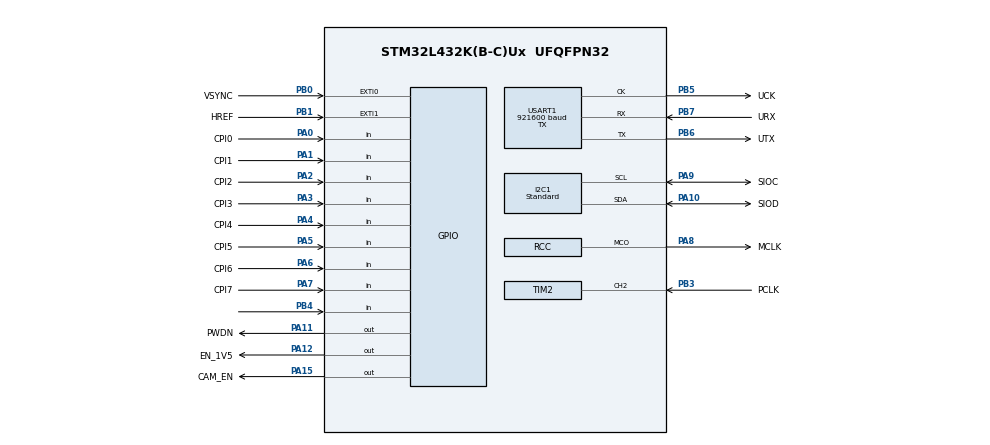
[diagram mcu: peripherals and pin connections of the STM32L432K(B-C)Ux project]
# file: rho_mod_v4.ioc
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Dma.Request0=TIM2_CH2/CH4
Dma.Request1=USART1_TX
Dma.TIM2_CH2/CH4.0.Direction=DMA_PERIPH_TO_MEMORY
Dma.TIM2_CH2/CH4.0.Instance=DMA1_Channel7
Dma.TIM2_CH2/CH4.0.MemDataAlignment=DMA_MDATAALIGN_BYTE
Dma.TIM2_CH2/CH4.0.MemInc=DMA_MINC_ENABLE
Dma.TIM2_CH2/CH4.0.Mode=DMA_CIRCULAR
Dma.TIM2_CH2/CH4.0.PeriphDataAlignment=DMA_PDATAALIGN_BYTE
Dma.TIM2_CH2/CH4.0.PeriphInc=DMA_PINC_DISABLE
Dma.TIM2_CH2/CH4.0.Priority=DMA_PRIORITY_VERY_HIGH
Dma.USART1_TX.1.Direction=DMA_MEMORY_TO_PERIPH
Dma.USART1_TX.1.Instance=DMA2_Channel6
Dma.USART1_TX.1.MemDataAlignment=DMA_MDATAALIGN_BYTE
Dma.USART1_TX.1.MemInc=DMA_MINC_ENABLE
Dma.USART1_TX.1.Mode=DMA_NORMAL
Dma.USART1_TX.1.PeriphDataAlignment=DMA_PDATAALIGN_BYTE
Dma.USART1_TX.1.PeriphInc=DMA_PINC_DISABLE
Dma.USART1_TX.1.Priority=DMA_PRIORITY_LOW
I2C1.I2C_Speed_Mode=I2C_Standard
I2C1.OwnAddress=0x60
I2C1.Timing=0x007074AF
Mcu.Family=STM32L4
Mcu.Name=STM32L432K(B-C)Ux
Mcu.Package=UFQFPN32
NVIC.DMA1_Channel7_IRQn=true\:0\:0\:false\:false\:true\:false
NVIC.DMA2_Channel6_IRQn=true\:0\:0\:false\:false\:true\:false
NVIC.EXTI0_IRQn=true\:1\:1\:true\:true\:true\:1\:true
NVIC.EXTI1_IRQn=true\:1\:1\:true\:true\:true\:2\:true
NVIC.PriorityGroup=NVIC_PRIORITYGROUP_2
NVIC.USART1_IRQn=true\:0\:0\:false\:false\:true\:true
PA0.GPIO_Label=CPI0
PA0.GPIO_Mode=GPIO_MODE_INPUT
PA0.GPIO_PuPd=GPIO_NOPULL
PA0.Signal=GPIO_Input
PA1.GPIO_Label=CPI1
PA1.GPIO_Mode=GPIO_MODE_INPUT
PA1.GPIO_PuPd=GPIO_NOPULL
PA1.Signal=GPIO_Input
PA10.GPIO_Label=SIOD
PA10.Mode=I2C
PA10.Signal=I2C1_SDA
PA11.GPIO_Label=PWDN
PA11.Signal=GPIO_Output
PA12.GPIO_Label=EN_1V5
PA12.Signal=GPIO_Output
PA15\ (JTDI).GPIO_Label=CAM_EN
PA15\ (JTDI).GPIO_ModeDefaultOutputPP=GPIO_MODE_OUTPUT_PP
PA15\ (JTDI).GPIO_PuPd=GPIO_PULLUP
PA15\ (JTDI).GPIO_Speed=GPIO_SPEED_FREQ_LOW
PA15\ (JTDI).PinState=GPIO_PIN_RESET
PA15\ (JTDI).Signal=GPIO_Output
PA2.GPIO_Label=CPI2
PA2.GPIO_Mode=GPIO_MODE_INPUT
PA2.GPIO_PuPd=GPIO_NOPULL
PA2.Signal=GPIO_Input
PA3.GPIO_Label=CPI3
PA3.GPIO_Mode=GPIO_MODE_INPUT
PA3.GPIO_PuPd=GPIO_NOPULL
PA3.Signal=GPIO_Input
PA4.GPIO_Label=CPI4
PA4.GPIO_Mode=GPIO_MODE_INPUT
PA4.GPIO_PuPd=GPIO_NOPULL
PA4.Signal=GPIO_Input
PA5.GPIO_Label=CPI5
PA5.GPIO_Mode=GPIO_MODE_INPUT
PA5.GPIO_PuPd=GPIO_NOPULL
PA5.Signal=GPIO_Input
PA6.GPIO_Label=CPI6
PA6.GPIO_Mode=GPIO_MODE_INPUT
PA6.GPIO_PuPd=GPIO_NOPULL
PA6.Signal=GPIO_Input
PA7.GPIO_Label=CPI7
PA7.GPIO_Mode=GPIO_MODE_INPUT
PA7.GPIO_PuPd=GPIO_NOPULL
PA7.Signal=GPIO_Input
PA8.GPIO_Label=MCLK
PA8.Mode=Clock-out
PA8.Signal=RCC_MCO
PA9.GPIO_Label=SIOC
PA9.Mode=I2C
PA9.Signal=I2C1_SCL
PB0.GPIO_Label=VSYNC
PB0.GPIO_ModeDefaultEXTI=GPIO_MODE_IT_RISING_FALLING
PB0.GPIO_PuPd=GPIO_PULLUP
PB0.Signal=GPXTI0
PB1.GPIO_Label=HREF
PB1.GPIO_ModeDefaultEXTI=GPIO_MODE_IT_RISING_FALLING
PB1.GPIO_PuPd=GPIO_PULLUP
PB1.Signal=GPXTI1
PB3\ (JTDO-TRACESWO).GPIO_Label=PCLK
PB3\ (JTDO-TRACESWO).GPIO_Speed=GPIO_SPEED_FREQ_VERY_HIGH
PB3\ (JTDO-TRACESWO).Signal=S_TIM2_CH2
PB4\ (NJTRST).Signal=GPIO_Input
PB5.GPIO_Label=UCK
PB5.Mode=Synchronous
PB5.Signal=USART1_CK
PB6.GPIO_FM6=I2C_FASTMODEPLUS_PB6
PB6.GPIO_Label=UTX
PB6.Mode=Synchronous
PB6.Signal=USART1_TX
PB7.GPIO_FM7=I2C_FASTMODEPLUS_PB7
PB7.GPIO_Label=URX
PB7.Mode=Synchronous
PB7.Signal=USART1_RX
PC14-OSC32_IN\ (PC14).Mode=LSE-External-Oscillator
PC14-OSC32_IN\ (PC14).Signal=RCC_OSC32_IN
PC15-OSC32_OUT\ (PC15).Mode=LSE-External-Oscillator
PC15-OSC32_OUT\ (PC15).Signal=RCC_OSC32_OUT
ProjectManager.HeapSize=0x200
ProjectManager.StackSize=0x400
ProjectManager.TargetToolchain=EWARM
RCC.ADCFreq_Value=60000000
RCC.AHBFreq_Value=30000000
RCC.APB1Freq_Value=30000000
RCC.APB1TimFreq_Value=30000000
RCC.APB2Freq_Value=30000000
RCC.APB2TimFreq_Value=30000000
RCC.CK48CLockSelection=RCC_USBCLKSOURCE_HSI48
RCC.CortexFreq_Value=30000000
RCC.FLatency-AdvancedSettings=FLASH_LATENCY_1
RCC.HCLKFreq_Value=30000000
RCC.HSE_VALUE=8000000
RCC.HSI48_VALUE=48000000
RCC.HSI_VALUE=16000000
RCC.I2C1CLockSelection=RCC_I2C1CLKSOURCE_SYSCLK
RCC.MSIClockRange=RCC_MSIRANGE_11
RCC.MSI_VALUE=48000000
RCC.PLLM=4
RCC.PLLN=10
RCC.PLLR=RCC_PLLR_DIV4
RCC.PLLSAI1N=10
RCC.RCC_MCO1Source=RCC_MCO1SOURCE_HSI
RCC.SYSCLKFreq_VALUE=30000000
RCC.SYSCLKSource=RCC_SYSCLKSOURCE_PLLCLK
RCC.USBFreq_Value=48000000
RCC.VCOOutputFreq_Value=120000000
SH.S_TIM2_CH2.0=TIM2_CH2,TriggerSource_TI2FP2
SH.S_TIM2_CH2.1=TIM2_CH2,Input_Capture2_from_TI2
TIM2.AutoReloadPreload=TIM_AUTORELOAD_PRELOAD_ENABLE
TIM2.Channel-Input_Capture2_from_TI2=TIM_CHANNEL_2
TIM2.CounterMode=TIM_COUNTERMODE_CENTERALIGNED1
TIM2.ICFilter_CH2=1
TIM2.ICPolarity_CH2=TIM_INPUTCHANNELPOLARITY_RISING
TIM2.Period=0
TIM2.TIM_MasterOutputTrigger=TIM_TRGO_RESET
USART1.BaudRate=921600
USART1.Mode=MODE_TX
USART1.VirtualMode-Synchronous=VM_SYNC
USART1.WordLength=WORDLENGTH_8B
VP_TIM2_VS_ControllerModeCombinedResetTrigger.Mode=Combined_Reset_Trigger_Mode
board=rho_mod_v4

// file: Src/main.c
/**
  ******************************************************************************
  * @file           : main.c
  * @brief          : Main program body
  ******************************************************************************
  ** This notice applies to any and all portions of this file
  * that are not between comment pairs USER CODE BEGIN and
  * USER CODE END. Other portions of this file, whether
  * inserted by the user or by software development tools
  * are owned by their respective copyright owners.
  *
  * COPYRIGHT(c) 2018 STMicroelectronics
  *
  * Redistribution and use in source and binary forms, with or without modification,
  * are permitted provided that the following conditions are met:
  *   1. Redistributions of source code must retain the above copyright notice,
  *      this list of conditions and the following disclaimer.
  *   2. Redistributions in binary form must reproduce the above copyright notice,
  *      this list of conditions and the following disclaimer in the documentation
  *      and/or other materials provided with the distribution.
  *   3. Neither the name of STMicroelectronics nor the names of its contributors
  *      may be used to endorse or promote products derived from this software
  *      without specific prior written permission.
  *
  * THIS SOFTWARE IS PROVIDED BY THE COPYRIGHT HOLDERS AND CONTRIBUTORS "AS IS"
  * AND ANY EXPRESS OR IMPLIED WARRANTIES, INCLUDING, BUT NOT LIMITED TO, THE
  * IMPLIED WARRANTIES OF MERCHANTABILITY AND FITNESS FOR A PARTICULAR PURPOSE ARE
  * DISCLAIMED. IN NO EVENT SHALL THE COPYRIGHT HOLDER OR CONTRIBUTORS BE LIABLE
  * FOR ANY DIRECT, INDIRECT, INCIDENTAL, SPECIAL, EXEMPLARY, OR CONSEQUENTIAL
  * DAMAGES (INCLUDING, BUT NOT LIMITED TO, PROCUREMENT OF SUBSTITUTE GOODS OR
  * SERVICES; LOSS OF USE, DATA, OR PROFITS; OR BUSINESS INTERRUPTION) HOWEVER
  * CAUSED AND ON ANY THEORY OF LIABILITY, WHETHER IN CONTRACT, STRICT LIABILITY,
  * OR TORT (INCLUDING NEGLIGENCE OR OTHERWISE) ARISING IN ANY WAY OUT OF THE USE
  * OF THIS SOFTWARE, EVEN IF ADVISED OF THE POSSIBILITY OF SUCH DAMAGE.
  *
  ******************************************************************************
  */
#include "main.h"
#include "stm32l4xx_hal.h"

/* USER CODE BEGIN Includes */
#include "master.h"
/* USER CODE END Includes */

I2C_HandleTypeDef hi2c1;

TIM_HandleTypeDef htim2;
DMA_HandleTypeDef hdma_tim2_ch2_ch4;

USART_HandleTypeDef husart1;
DMA_HandleTypeDef hdma_usart1_tx;

/* USER CODE BEGIN PV */
/* Private variables ---------------------------------------------------------*/

/* USER CODE END PV */

void SystemClock_Config(void);
static void MX_GPIO_Init(void);
static void MX_DMA_Init(void);
static void MX_I2C1_Init(void);
static void MX_USART1_Init(void);
static void MX_TIM2_Init(void);
static void MX_NVIC_Init(void);

/* USER CODE BEGIN PFP */
/* Private function prototypes -----------------------------------------------*/

/* USER CODE END PFP */

int main(void)
{

  /* MCU Configuration----------------------------------------------------------*/

  /* Reset of all peripherals, Initializes the Flash interface and the Systick. */
  HAL_Init();

  /* Configure the system clock */
  SystemClock_Config();

  /* Initialize all configured peripherals */
  MX_GPIO_Init();
  MX_DMA_Init();
  MX_I2C1_Init();
  MX_USART1_Init();
  MX_TIM2_Init();

  /* Initialize interrupts */
  MX_NVIC_Init();
  /* USER CODE BEGIN 2 */
  master_init( &hi2c1, &htim2, &husart1 );
  /* USER CODE END 2 */

  /* Infinite loop */
  while (1)
  {

  }

}

void SystemClock_Config(void)
{

  RCC_OscInitTypeDef RCC_OscInitStruct;
  RCC_ClkInitTypeDef RCC_ClkInitStruct;
  RCC_PeriphCLKInitTypeDef PeriphClkInit;

    /**Configure LSE Drive Capability
    */
  HAL_PWR_EnableBkUpAccess();

  __HAL_RCC_LSEDRIVE_CONFIG(RCC_LSEDRIVE_LOW);

    /**Initializes the CPU, AHB and APB busses clocks
    */
  RCC_OscInitStruct.OscillatorType = RCC_OSCILLATORTYPE_HSI|RCC_OSCILLATORTYPE_LSE
                              |RCC_OSCILLATORTYPE_MSI;
  RCC_OscInitStruct.LSEState = RCC_LSE_ON;
  RCC_OscInitStruct.HSIState = RCC_HSI_ON;
  RCC_OscInitStruct.HSICalibrationValue = 16;
  RCC_OscInitStruct.MSIState = RCC_MSI_ON;
  RCC_OscInitStruct.MSICalibrationValue = 0;
  RCC_OscInitStruct.MSIClockRange = RCC_MSIRANGE_11;
  RCC_OscInitStruct.PLL.PLLState = RCC_PLL_ON;
  RCC_OscInitStruct.PLL.PLLSource = RCC_PLLSOURCE_MSI;
  RCC_OscInitStruct.PLL.PLLN = 10;
  RCC_OscInitStruct.PLL.PLLP = RCC_PLLP_DIV7;
  RCC_OscInitStruct.PLL.PLLQ = RCC_PLLQ_DIV2;
  RCC_OscInitStruct.PLL.PLLR = RCC_PLLR_DIV4;
  if (HAL_RCC_OscConfig(&RCC_OscInitStruct) != HAL_OK)
  {
    _Error_Handler(__FILE__, __LINE__);
  }

    /**Initializes the CPU, AHB and APB busses clocks
    */
  RCC_ClkInitStruct.ClockType = RCC_CLOCKTYPE_HCLK|RCC_CLOCKTYPE_SYSCLK
                              |RCC_CLOCKTYPE_PCLK1|RCC_CLOCKTYPE_PCLK2;
  RCC_ClkInitStruct.SYSCLKSource = RCC_SYSCLKSOURCE_PLLCLK;
  RCC_ClkInitStruct.AHBCLKDivider = RCC_SYSCLK_DIV1;
  RCC_ClkInitStruct.APB1CLKDivider = RCC_HCLK_DIV1;
  RCC_ClkInitStruct.APB2CLKDivider = RCC_HCLK_DIV1;

  if (HAL_RCC_ClockConfig(&RCC_ClkInitStruct, FLASH_LATENCY_1) != HAL_OK)
  {
    _Error_Handler(__FILE__, __LINE__);
  }

  PeriphClkInit.PeriphClockSelection = RCC_PERIPHCLK_USART1|RCC_PERIPHCLK_I2C1;
  PeriphClkInit.Usart1ClockSelection = RCC_USART1CLKSOURCE_PCLK2;
  PeriphClkInit.I2c1ClockSelection = RCC_I2C1CLKSOURCE_SYSCLK;
  if (HAL_RCCEx_PeriphCLKConfig(&PeriphClkInit) != HAL_OK)
  {
    _Error_Handler(__FILE__, __LINE__);
  }

  HAL_RCC_MCOConfig(RCC_MCO1, RCC_MCO1SOURCE_HSI, RCC_MCODIV_1);

    /**Configure the main internal regulator output voltage
    */
  if (HAL_PWREx_ControlVoltageScaling(PWR_REGULATOR_VOLTAGE_SCALE1) != HAL_OK)
  {
    _Error_Handler(__FILE__, __LINE__);
  }

    /**Configure the Systick interrupt time
    */
  HAL_SYSTICK_Config(HAL_RCC_GetHCLKFreq()/1000);

    /**Configure the Systick
    */
  HAL_SYSTICK_CLKSourceConfig(SYSTICK_CLKSOURCE_HCLK);

    /**Enable MSI Auto calibration
    */
  HAL_RCCEx_EnableMSIPLLMode();

  /* SysTick_IRQn interrupt configuration */
  HAL_NVIC_SetPriority(SysTick_IRQn, 0, 0);
}

/**
  * @brief NVIC Configuration.
  * @retval None
  */
static void MX_NVIC_Init(void)
{
  /* EXTI0_IRQn interrupt configuration */
  HAL_NVIC_SetPriority(EXTI0_IRQn, 1, 1);
  HAL_NVIC_EnableIRQ(EXTI0_IRQn);
  /* EXTI1_IRQn interrupt configuration */
  HAL_NVIC_SetPriority(EXTI1_IRQn, 1, 1);
  HAL_NVIC_EnableIRQ(EXTI1_IRQn);
}

/* I2C1 init function */
static void MX_I2C1_Init(void)
{

  hi2c1.Instance = I2C1;
  hi2c1.Init.Timing = 0x007074AF;
  hi2c1.Init.OwnAddress1 = 192;
  hi2c1.Init.AddressingMode = I2C_ADDRESSINGMODE_7BIT;
  hi2c1.Init.DualAddressMode = I2C_DUALADDRESS_DISABLE;
  hi2c1.Init.OwnAddress2 = 0;
  hi2c1.Init.OwnAddress2Masks = I2C_OA2_NOMASK;
  hi2c1.Init.GeneralCallMode = I2C_GENERALCALL_DISABLE;
  hi2c1.Init.NoStretchMode = I2C_NOSTRETCH_DISABLE;
  if (HAL_I2C_Init(&hi2c1) != HAL_OK)
  {
    _Error_Handler(__FILE__, __LINE__);
  }

    /**Configure Analogue filter
    */
  if (HAL_I2CEx_ConfigAnalogFilter(&hi2c1, I2C_ANALOGFILTER_ENABLE) != HAL_OK)
  {
    _Error_Handler(__FILE__, __LINE__);
  }

    /**Configure Digital filter
    */
  if (HAL_I2CEx_ConfigDigitalFilter(&hi2c1, 0) != HAL_OK)
  {
    _Error_Handler(__FILE__, __LINE__);
  }

}

/* TIM2 init function */
static void MX_TIM2_Init(void)
{

  TIM_SlaveConfigTypeDef sSlaveConfig;
  TIM_MasterConfigTypeDef sMasterConfig;
  TIM_IC_InitTypeDef sConfigIC;

  htim2.Instance = TIM2;
  htim2.Init.Prescaler = 0;
  htim2.Init.CounterMode = TIM_COUNTERMODE_CENTERALIGNED1;
  htim2.Init.Period = 0;
  htim2.Init.ClockDivision = TIM_CLOCKDIVISION_DIV1;
  htim2.Init.AutoReloadPreload = TIM_AUTORELOAD_PRELOAD_ENABLE;
  if (HAL_TIM_Base_Init(&htim2) != HAL_OK)
  {
    _Error_Handler(__FILE__, __LINE__);
  }

  if (HAL_TIM_IC_Init(&htim2) != HAL_OK)
  {
    _Error_Handler(__FILE__, __LINE__);
  }

  sSlaveConfig.SlaveMode = TIM_SLAVEMODE_COMBINED_RESETTRIGGER;
  sSlaveConfig.InputTrigger = TIM_TS_TI2FP2;
  sSlaveConfig.TriggerPolarity = TIM_INPUTCHANNELPOLARITY_RISING;
  sSlaveConfig.TriggerFilter = 0;
  if (HAL_TIM_SlaveConfigSynchronization(&htim2, &sSlaveConfig) != HAL_OK)
  {
    _Error_Handler(__FILE__, __LINE__);
  }

  sMasterConfig.MasterOutputTrigger = TIM_TRGO_RESET;
  sMasterConfig.MasterSlaveMode = TIM_MASTERSLAVEMODE_DISABLE;
  if (HAL_TIMEx_MasterConfigSynchronization(&htim2, &sMasterConfig) != HAL_OK)
  {
    _Error_Handler(__FILE__, __LINE__);
  }

  sConfigIC.ICPolarity = TIM_INPUTCHANNELPOLARITY_RISING;
  sConfigIC.ICSelection = TIM_ICSELECTION_DIRECTTI;
  sConfigIC.ICPrescaler = TIM_ICPSC_DIV1;
  sConfigIC.ICFilter = 1;
  if (HAL_TIM_IC_ConfigChannel(&htim2, &sConfigIC, TIM_CHANNEL_2) != HAL_OK)
  {
    _Error_Handler(__FILE__, __LINE__);
  }

}

/* USART1 init function */
static void MX_USART1_Init(void)
{

  husart1.Instance = USART1;
  husart1.Init.BaudRate = 921600;
  husart1.Init.WordLength = USART_WORDLENGTH_8B;
  husart1.Init.StopBits = USART_STOPBITS_1;
  husart1.Init.Parity = USART_PARITY_NONE;
  husart1.Init.Mode = USART_MODE_TX;
  husart1.Init.CLKPolarity = USART_POLARITY_LOW;
  husart1.Init.CLKPhase = USART_PHASE_1EDGE;
  husart1.Init.CLKLastBit = USART_LASTBIT_DISABLE;
  if (HAL_USART_Init(&husart1) != HAL_OK)
  {
    _Error_Handler(__FILE__, __LINE__);
  }

}

static void MX_DMA_Init(void)
{
  /* DMA controller clock enable */
  __HAL_RCC_DMA1_CLK_ENABLE();
  __HAL_RCC_DMA2_CLK_ENABLE();

  /* DMA interrupt init */
  /* DMA1_Channel7_IRQn interrupt configuration */
  HAL_NVIC_SetPriority(DMA1_Channel7_IRQn, 0, 0);
  HAL_NVIC_EnableIRQ(DMA1_Channel7_IRQn);
  /* DMA2_Channel6_IRQn interrupt configuration */
  HAL_NVIC_SetPriority(DMA2_Channel6_IRQn, 0, 0);
  HAL_NVIC_EnableIRQ(DMA2_Channel6_IRQn);

}

/** Configure pins as
        * Analog
        * Input
        * Output
        * EVENT_OUT
        * EXTI
     PA8   ------> RCC_MCO
*/
static void MX_GPIO_Init(void)
{

  GPIO_InitTypeDef GPIO_InitStruct;

  /* GPIO Ports Clock Enable */
  __HAL_RCC_GPIOC_CLK_ENABLE();
  __HAL_RCC_GPIOA_CLK_ENABLE();
  __HAL_RCC_GPIOB_CLK_ENABLE();

  /*Configure GPIO pin Output Level */
  HAL_GPIO_WritePin(GPIOA, PWDN_Pin|EN_1V5_Pin|CAM_EN_Pin, GPIO_PIN_RESET);

  /*Configure GPIO pins : CPI0_Pin CPI1_Pin CPI2_Pin CPI3_Pin
                           CPI4_Pin CPI5_Pin CPI6_Pin CPI7_Pin */
  GPIO_InitStruct.Pin = CPI0_Pin|CPI1_Pin|CPI2_Pin|CPI3_Pin
                          |CPI4_Pin|CPI5_Pin|CPI6_Pin|CPI7_Pin;
  GPIO_InitStruct.Mode = GPIO_MODE_INPUT;
  GPIO_InitStruct.Pull = GPIO_NOPULL;
  HAL_GPIO_Init(GPIOA, &GPIO_InitStruct);

  /*Configure GPIO pins : VSYNC_Pin HREF_Pin */
  GPIO_InitStruct.Pin = VSYNC_Pin|HREF_Pin;
  GPIO_InitStruct.Mode = GPIO_MODE_IT_RISING_FALLING;
  GPIO_InitStruct.Pull = GPIO_PULLUP;
  HAL_GPIO_Init(GPIOB, &GPIO_InitStruct);

  /*Configure GPIO pin : MCLK_Pin */
  GPIO_InitStruct.Pin = MCLK_Pin;
  GPIO_InitStruct.Mode = GPIO_MODE_AF_PP;
  GPIO_InitStruct.Pull = GPIO_NOPULL;
  GPIO_InitStruct.Speed = GPIO_SPEED_FREQ_LOW;
  GPIO_InitStruct.Alternate = GPIO_AF0_MCO;
  HAL_GPIO_Init(MCLK_GPIO_Port, &GPIO_InitStruct);

  /*Configure GPIO pins : PWDN_Pin EN_1V5_Pin */
  GPIO_InitStruct.Pin = PWDN_Pin|EN_1V5_Pin;
  GPIO_InitStruct.Mode = GPIO_MODE_OUTPUT_PP;
  GPIO_InitStruct.Pull = GPIO_NOPULL;
  GPIO_InitStruct.Speed = GPIO_SPEED_FREQ_LOW;
  HAL_GPIO_Init(GPIOA, &GPIO_InitStruct);

  /*Configure GPIO pin : CAM_EN_Pin */
  GPIO_InitStruct.Pin = CAM_EN_Pin;
  GPIO_InitStruct.Mode = GPIO_MODE_OUTPUT_PP;
  GPIO_InitStruct.Pull = GPIO_PULLUP;
  GPIO_InitStruct.Speed = GPIO_SPEED_FREQ_LOW;
  HAL_GPIO_Init(CAM_EN_GPIO_Port, &GPIO_InitStruct);

  /*Configure GPIO pin : PB4 */
  GPIO_InitStruct.Pin = GPIO_PIN_4;
  GPIO_InitStruct.Mode = GPIO_MODE_INPUT;
  GPIO_InitStruct.Pull = GPIO_NOPULL;
  HAL_GPIO_Init(GPIOB, &GPIO_InitStruct);

}

void _Error_Handler(char *file, int line)
{
  while(1)
  {
  }
}

/************************ (C) COPYRIGHT STMicroelectronics *****END OF FILE****/
